# cml_gate2 : LEF d'integration unique MSPHY5973 / MSPHY4263 (alim-cml et prompt-063-leo, 29/09/2026). PIN du LEF source cml_gate2_env.lef,
# OBS recalculees depuis le metal reel du GDS (Metal1 a Metal5, vias compris), moins les PIN de la meme couche, sur le GDS enveloppe (piles et bandes d'alimentation d'alim-cml) ;
# OBS TopMetal1 = boite moins les bandes TopMetal1 VDD / VSS (broches).
VERSION 5.7 ;
  NOWIREEXTENSIONATPIN ON ;
  DIVIDERCHAR "/" ;
  BUSBITCHARS "[]" ;
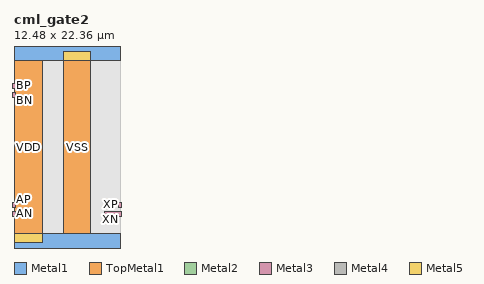
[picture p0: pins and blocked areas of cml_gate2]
MACRO cml_gate2
  CLASS BLOCK ;
  FOREIGN cml_gate2 ;
  ORIGIN 0.000 0.000 ;
  SIZE 12.480 BY 22.360 ;
  PIN VDD
    DIRECTION INOUT ;
    USE POWER ;
    PORT
      LAYER Metal1 ;
        RECT 0.000 -1.000 12.480 1.000 ;
      LAYER TopMetal1 ;
        RECT 0.100 -0.000 3.300 22.360 ;
      LAYER Metal2 ;
        RECT 0.100 0.000 3.300 1.020 ;
      LAYER Metal3 ;
        RECT 0.100 0.000 3.300 1.020 ;
      LAYER Metal4 ;
        RECT 0.100 0.000 3.300 1.020 ;
      LAYER Metal5 ;
        RECT 0.100 0.000 3.300 1.020 ;
    END
  END VDD
  PIN VSS
    DIRECTION INOUT ;
    USE GROUND ;
    PORT
      LAYER Metal1 ;
        RECT 0.000 21.360 12.480 23.360 ;
      LAYER TopMetal1 ;
        RECT 5.860 -0.000 9.060 22.360 ;
      LAYER Metal2 ;
        RECT 5.860 21.360 9.060 22.380 ;
      LAYER Metal3 ;
        RECT 5.860 21.360 9.060 22.380 ;
      LAYER Metal4 ;
        RECT 5.860 21.360 9.060 22.380 ;
      LAYER Metal5 ;
        RECT 5.860 21.360 9.060 22.380 ;
    END
  END VSS
  PIN AN
    DIRECTION INPUT ;
    USE SIGNAL ;
    ANTENNAGATEAREA 0.826800 ;
    PORT
      LAYER Metal3 ;
        RECT -0.150 3.000 0.150 3.600 ;
    END
  END AN
  PIN AP
    DIRECTION INPUT ;
    USE SIGNAL ;
    ANTENNAGATEAREA 0.826800 ;
    PORT
      LAYER Metal3 ;
        RECT -0.150 4.100 0.150 4.700 ;
    END
  END AP
  PIN XN
    DIRECTION OUTPUT ;
    USE SIGNAL ;
    ANTENNADIFFAREA 1.208400 ;
    PORT
      LAYER Metal3 ;
        RECT 10.685 3.000 12.630 3.600 ;
    END
  END XN
  PIN XP
    DIRECTION OUTPUT ;
    USE SIGNAL ;
    ANTENNADIFFAREA 2.416800 ;
    PORT
      LAYER Metal3 ;
        RECT 12.330 4.100 12.630 4.700 ;
    END
  END XP
  PIN BN
    DIRECTION INPUT ;
    USE SIGNAL ;
    ANTENNAGATEAREA 0.826800 ;
    PORT
      LAYER Metal3 ;
        RECT -0.150 17.000 0.150 17.600 ;
    END
  END BN
  PIN BP
    DIRECTION INPUT ;
    USE SIGNAL ;
    ANTENNAGATEAREA 0.826800 ;
    PORT
      LAYER Metal3 ;
        RECT -0.150 18.100 0.150 18.700 ;
    END
  END BP
  OBS
    LAYER Metal1 ;
      RECT 2.030 2.135 2.420 2.465 ;
      RECT 2.025 2.150 2.030 2.410 ;
      RECT 4.230 2.150 4.235 2.410 ;
      RECT 3.840 2.135 4.230 2.465 ;
      RECT 6.720 2.340 7.680 2.655 ;
      RECT 10.070 2.340 11.030 2.655 ;
      RECT 2.030 2.645 2.420 2.975 ;
      RECT 2.025 2.660 2.030 2.920 ;
      RECT 4.230 2.660 4.235 2.920 ;
      RECT 3.840 2.645 4.230 2.975 ;
      RECT 2.030 3.155 2.420 3.485 ;
      RECT 2.025 3.170 2.030 3.430 ;
      RECT 4.230 3.170 4.235 3.430 ;
      RECT 3.840 3.155 4.230 3.485 ;
      RECT 2.030 3.665 2.420 3.995 ;
      RECT 2.025 3.680 2.030 3.940 ;
      RECT 4.230 3.680 4.235 3.940 ;
      RECT 3.840 3.665 4.230 3.995 ;
      RECT 2.030 4.175 2.420 4.505 ;
      RECT 2.025 4.190 2.030 4.450 ;
      RECT 4.230 4.190 4.235 4.450 ;
      RECT 3.840 4.175 4.230 4.505 ;
      RECT 2.030 4.685 2.420 5.015 ;
      RECT 2.025 4.700 2.030 4.960 ;
      RECT 4.230 4.700 4.235 4.960 ;
      RECT 3.840 4.685 4.230 5.015 ;
      RECT 2.030 5.195 2.420 5.525 ;
      RECT 2.025 5.210 2.030 5.470 ;
      RECT 4.230 5.210 4.235 5.470 ;
      RECT 3.840 5.195 4.230 5.525 ;
      RECT 2.030 5.705 2.420 6.035 ;
      RECT 2.025 5.720 2.030 5.980 ;
      RECT 4.230 5.720 4.235 5.980 ;
      RECT 3.840 5.705 4.230 6.035 ;
      RECT 2.030 6.215 2.420 6.545 ;
      RECT 2.025 6.230 2.030 6.490 ;
      RECT 4.230 6.230 4.235 6.490 ;
      RECT 3.840 6.215 4.230 6.545 ;
      RECT 2.030 6.725 2.420 7.055 ;
      RECT 2.025 6.740 2.030 7.000 ;
      RECT 4.230 6.740 4.235 7.000 ;
      RECT 3.840 6.725 4.230 7.055 ;
      RECT 2.030 7.235 2.420 7.565 ;
      RECT 2.025 7.250 2.030 7.510 ;
      RECT 4.230 7.250 4.235 7.510 ;
      RECT 3.840 7.235 4.230 7.565 ;
      RECT 2.030 7.745 2.420 8.075 ;
      RECT 2.025 7.760 2.030 8.020 ;
      RECT 4.230 7.760 4.235 8.020 ;
      RECT 3.840 7.745 4.230 8.075 ;
      RECT 2.030 8.255 2.420 8.585 ;
      RECT 2.025 8.270 2.030 8.530 ;
      RECT 4.230 8.270 4.235 8.530 ;
      RECT 3.840 8.255 4.230 8.585 ;
      RECT 1.655 1.900 1.815 8.780 ;
      RECT 1.655 8.780 2.785 8.940 ;
      RECT 2.625 1.900 2.785 8.780 ;
      RECT 1.655 1.590 2.785 1.900 ;
      RECT 3.475 1.900 3.635 8.780 ;
      RECT 3.475 8.780 4.605 8.940 ;
      RECT 4.445 1.900 4.605 8.780 ;
      RECT 3.475 1.590 4.605 1.900 ;
      RECT 2.040 9.790 2.430 10.120 ;
      RECT 2.035 9.820 2.040 10.080 ;
      RECT 4.240 9.820 4.245 10.080 ;
      RECT 3.850 9.790 4.240 10.120 ;
      RECT 6.720 10.265 7.680 10.580 ;
      RECT 10.070 10.265 11.030 10.580 ;
      RECT 2.040 10.300 2.430 10.630 ;
      RECT 2.035 10.330 2.040 10.590 ;
      RECT 4.240 10.330 4.245 10.590 ;
      RECT 3.850 10.300 4.240 10.630 ;
      RECT 2.040 10.810 2.430 11.140 ;
      RECT 2.035 10.840 2.040 11.100 ;
      RECT 4.240 10.840 4.245 11.100 ;
      RECT 3.850 10.810 4.240 11.140 ;
      RECT 2.040 11.320 2.430 11.650 ;
      RECT 2.035 11.350 2.040 11.610 ;
      RECT 4.240 11.350 4.245 11.610 ;
      RECT 3.850 11.320 4.240 11.650 ;
      RECT 2.040 11.830 2.430 12.160 ;
      RECT 2.035 11.860 2.040 12.120 ;
      RECT 4.240 11.860 4.245 12.120 ;
      RECT 3.850 11.830 4.240 12.160 ;
      RECT 2.040 12.340 2.430 12.670 ;
      RECT 2.035 12.370 2.040 12.630 ;
      RECT 4.240 12.370 4.245 12.630 ;
      RECT 3.850 12.340 4.240 12.670 ;
      RECT 2.040 12.850 2.430 13.180 ;
      RECT 2.035 12.880 2.040 13.140 ;
      RECT 4.240 12.880 4.245 13.140 ;
      RECT 3.850 12.850 4.240 13.180 ;
      RECT 2.040 13.360 2.430 13.690 ;
      RECT 2.035 13.390 2.040 13.650 ;
      RECT 4.240 13.390 4.245 13.650 ;
      RECT 3.850 13.360 4.240 13.690 ;
      RECT 2.040 13.870 2.430 14.200 ;
      RECT 2.035 13.900 2.040 14.160 ;
      RECT 4.240 13.900 4.245 14.160 ;
      RECT 3.850 13.870 4.240 14.200 ;
      RECT 2.040 14.380 2.430 14.710 ;
      RECT 2.035 14.410 2.040 14.670 ;
      RECT 4.240 14.410 4.245 14.670 ;
      RECT 3.850 14.380 4.240 14.710 ;
      RECT 2.040 14.890 2.430 15.220 ;
      RECT 2.035 14.920 2.040 15.180 ;
      RECT 4.240 14.920 4.245 15.180 ;
      RECT 3.850 14.890 4.240 15.220 ;
      RECT 2.040 15.400 2.430 15.730 ;
      RECT 2.035 15.430 2.040 15.690 ;
      RECT 4.240 15.430 4.245 15.690 ;
      RECT 3.850 15.400 4.240 15.730 ;
      RECT 2.040 15.910 2.430 16.240 ;
      RECT 2.035 15.940 2.040 16.200 ;
      RECT 4.240 15.940 4.245 16.200 ;
      RECT 3.850 15.910 4.240 16.240 ;
      RECT 3.485 9.570 3.645 16.450 ;
      RECT 3.650 16.450 4.615 16.660 ;
      RECT 4.455 9.570 4.615 16.450 ;
      RECT 3.485 9.400 4.615 9.570 ;
      RECT 3.485 16.450 3.650 17.150 ;
      RECT 3.450 17.150 3.680 17.450 ;
      RECT 1.665 9.570 1.825 16.450 ;
      RECT 1.650 16.450 2.795 16.660 ;
      RECT 2.635 9.570 2.795 16.450 ;
      RECT 1.665 9.400 2.795 9.570 ;
      RECT 1.490 16.450 1.650 18.100 ;
      RECT 1.450 18.100 1.680 18.400 ;
      RECT 2.690 19.030 3.005 19.990 ;
      RECT 6.060 1.840 6.220 11.080 ;
      RECT 8.180 1.840 8.340 11.080 ;
      RECT 9.410 1.840 9.570 11.080 ;
      RECT 2.030 18.530 2.190 20.490 ;
      RECT 2.030 20.650 2.460 21.360 ;
      RECT 6.060 11.080 11.690 11.240 ;
      RECT 11.530 1.840 11.690 11.080 ;
      RECT 6.060 1.680 11.690 1.840 ;
      RECT 2.030 20.490 8.055 20.650 ;
      RECT 8.055 19.030 8.870 21.360 ;
      RECT 8.870 18.370 9.030 21.360 ;
      RECT 2.030 18.370 8.870 18.530 ;
      RECT 6.060 11.240 6.280 18.370 ;
    LAYER Via1 ;
      RECT 8.105 19.210 8.295 19.400 ;
      RECT 8.105 19.620 8.295 19.810 ;
      RECT 6.165 21.535 6.355 21.725 ;
      RECT 6.645 21.535 6.835 21.725 ;
      RECT 7.125 21.535 7.315 21.725 ;
      RECT 7.605 21.535 7.795 21.725 ;
      RECT 8.085 21.535 8.275 21.725 ;
      RECT 8.565 21.535 8.755 21.725 ;
      RECT 6.165 22.015 6.355 22.205 ;
      RECT 6.645 22.015 6.835 22.205 ;
      RECT 7.125 22.015 7.315 22.205 ;
      RECT 7.605 22.015 7.795 22.205 ;
      RECT 8.085 22.015 8.275 22.205 ;
      RECT 8.565 22.015 8.755 22.205 ;
      RECT 2.140 14.955 2.330 15.145 ;
      RECT 3.950 14.955 4.140 15.145 ;
      RECT 2.140 15.465 2.330 15.655 ;
      RECT 3.950 15.465 4.140 15.655 ;
      RECT 2.140 15.975 2.330 16.165 ;
      RECT 3.950 15.975 4.140 16.165 ;
      RECT 3.475 17.205 3.665 17.395 ;
      RECT 1.475 18.155 1.665 18.345 ;
      RECT 2.765 19.210 2.955 19.400 ;
      RECT 2.140 11.385 2.330 11.575 ;
      RECT 2.765 19.620 2.955 19.810 ;
      RECT 3.950 11.385 4.140 11.575 ;
      RECT 2.140 11.895 2.330 12.085 ;
      RECT 3.950 11.895 4.140 12.085 ;
      RECT 2.140 12.405 2.330 12.595 ;
      RECT 3.950 12.405 4.140 12.595 ;
      RECT 2.140 12.915 2.330 13.105 ;
      RECT 3.950 12.915 4.140 13.105 ;
      RECT 2.140 13.425 2.330 13.615 ;
      RECT 3.950 13.425 4.140 13.615 ;
      RECT 2.140 13.935 2.330 14.125 ;
      RECT 3.950 13.935 4.140 14.125 ;
      RECT 2.140 14.445 2.330 14.635 ;
      RECT 3.950 14.445 4.140 14.635 ;
      RECT 2.130 7.810 2.320 8.000 ;
      RECT 3.940 7.810 4.130 8.000 ;
      RECT 2.130 8.320 2.320 8.510 ;
      RECT 3.940 8.320 4.130 8.510 ;
      RECT 2.140 9.855 2.330 10.045 ;
      RECT 3.950 9.855 4.140 10.045 ;
      RECT 2.140 10.365 2.330 10.555 ;
      RECT 3.950 10.365 4.140 10.555 ;
      RECT 2.140 10.875 2.330 11.065 ;
      RECT 3.950 10.875 4.140 11.065 ;
      RECT 0.405 0.175 0.595 0.365 ;
      RECT 0.885 0.175 1.075 0.365 ;
      RECT 1.365 0.175 1.555 0.365 ;
      RECT 1.845 0.175 2.035 0.365 ;
      RECT 2.325 0.175 2.515 0.365 ;
      RECT 2.805 0.175 2.995 0.365 ;
      RECT 0.405 0.655 0.595 0.845 ;
      RECT 0.885 0.655 1.075 0.845 ;
      RECT 1.365 0.655 1.555 0.845 ;
      RECT 1.845 0.655 2.035 0.845 ;
      RECT 2.325 0.655 2.515 0.845 ;
      RECT 2.805 0.655 2.995 0.845 ;
      RECT 1.760 1.660 1.950 1.850 ;
      RECT 2.200 1.660 2.390 1.850 ;
      RECT 3.540 1.660 3.730 1.850 ;
      RECT 3.980 1.660 4.170 1.850 ;
      RECT 2.130 2.200 2.320 2.390 ;
      RECT 3.940 2.200 4.130 2.390 ;
      RECT 2.130 2.710 2.320 2.900 ;
      RECT 3.940 2.710 4.130 2.900 ;
      RECT 2.130 3.220 2.320 3.410 ;
      RECT 3.940 3.220 4.130 3.410 ;
      RECT 2.130 3.730 2.320 3.920 ;
      RECT 3.940 3.730 4.130 3.920 ;
      RECT 2.130 4.240 2.320 4.430 ;
      RECT 3.940 4.240 4.130 4.430 ;
      RECT 2.130 4.750 2.320 4.940 ;
      RECT 3.940 4.750 4.130 4.940 ;
      RECT 2.130 5.260 2.320 5.450 ;
      RECT 3.940 5.260 4.130 5.450 ;
      RECT 2.130 5.770 2.320 5.960 ;
      RECT 3.940 5.770 4.130 5.960 ;
      RECT 2.130 6.280 2.320 6.470 ;
      RECT 3.940 6.280 4.130 6.470 ;
      RECT 2.130 6.790 2.320 6.980 ;
      RECT 3.940 6.790 4.130 6.980 ;
      RECT 2.130 7.300 2.320 7.490 ;
      RECT 3.940 7.300 4.130 7.490 ;
      RECT 10.135 0.705 10.325 0.895 ;
      RECT 10.775 0.705 10.965 0.895 ;
      RECT 6.900 10.315 7.090 10.505 ;
      RECT 7.310 10.315 7.500 10.505 ;
      RECT 10.250 10.315 10.440 10.505 ;
      RECT 10.660 10.315 10.850 10.505 ;
      RECT 10.135 0.285 10.325 0.475 ;
      RECT 10.775 0.285 10.965 0.475 ;
      RECT 6.785 0.285 6.975 0.475 ;
      RECT 7.425 0.285 7.615 0.475 ;
      RECT 6.785 0.705 6.975 0.895 ;
      RECT 7.425 0.705 7.615 0.895 ;
      RECT 6.900 2.415 7.090 2.605 ;
      RECT 7.310 2.415 7.500 2.605 ;
      RECT 10.250 2.415 10.440 2.605 ;
      RECT 10.660 2.415 10.850 2.605 ;
    LAYER Metal2 ;
      RECT 2.910 1.620 4.230 1.890 ;
      RECT 6.770 0.230 7.630 2.695 ;
      RECT 10.120 0.230 10.980 2.695 ;
      RECT 0.400 1.610 2.450 1.900 ;
      RECT 0.400 1.900 0.710 4.400 ;
      RECT 1.370 4.735 2.380 4.955 ;
      RECT 1.370 6.775 2.380 6.995 ;
      RECT 1.370 5.755 2.380 5.975 ;
      RECT 1.370 3.715 2.380 3.935 ;
      RECT 1.150 2.695 2.380 2.915 ;
      RECT 1.150 2.915 1.370 7.795 ;
      RECT 1.000 2.915 1.150 6.995 ;
      RECT 1.150 7.795 2.380 8.015 ;
      RECT 10.120 10.225 10.980 10.595 ;
      RECT 10.400 3.000 10.750 10.225 ;
      RECT 1.380 8.305 4.190 8.525 ;
      RECT 1.380 8.525 3.350 8.670 ;
      RECT 2.910 7.505 3.350 8.305 ;
      RECT 2.070 7.285 4.190 7.505 ;
      RECT 2.910 6.485 3.350 7.285 ;
      RECT 2.070 6.265 4.190 6.485 ;
      RECT 2.910 5.465 3.350 6.265 ;
      RECT 2.070 5.245 4.190 5.465 ;
      RECT 2.910 4.445 3.350 5.245 ;
      RECT 2.070 4.225 4.190 4.445 ;
      RECT 2.910 3.425 3.350 4.225 ;
      RECT 2.070 3.205 4.190 3.425 ;
      RECT 2.910 2.405 3.350 3.205 ;
      RECT 2.070 2.185 4.190 2.405 ;
      RECT 1.380 11.370 2.390 11.590 ;
      RECT 1.380 14.430 2.390 14.650 ;
      RECT 1.380 13.410 2.390 13.630 ;
      RECT 1.380 12.390 2.390 12.610 ;
      RECT 1.380 10.350 2.390 10.570 ;
      RECT 1.060 8.305 1.380 15.450 ;
      RECT 1.060 15.450 2.390 15.670 ;
      RECT 5.270 10.110 7.720 10.680 ;
      RECT 3.880 3.715 4.900 3.935 ;
      RECT 3.880 4.735 4.900 4.955 ;
      RECT 3.880 5.755 4.900 5.975 ;
      RECT 3.880 6.775 4.900 6.995 ;
      RECT 3.880 7.795 4.900 8.015 ;
      RECT 3.890 10.350 4.900 10.570 ;
      RECT 3.890 11.370 4.900 11.590 ;
      RECT 3.890 12.390 4.900 12.610 ;
      RECT 3.890 13.410 4.900 13.630 ;
      RECT 3.890 14.430 4.900 14.650 ;
      RECT 3.890 15.450 5.270 15.670 ;
      RECT 4.900 2.915 5.270 15.450 ;
      RECT 3.880 2.695 5.270 2.915 ;
      RECT 3.410 17.150 3.720 17.650 ;
      RECT 1.410 18.100 1.720 18.600 ;
      RECT 2.080 15.960 4.200 16.180 ;
      RECT 2.920 15.160 3.360 15.960 ;
      RECT 2.080 14.940 4.200 15.160 ;
      RECT 2.675 19.080 3.190 19.940 ;
      RECT 2.750 16.180 3.190 19.080 ;
      RECT 2.920 14.140 3.360 14.940 ;
      RECT 2.080 13.920 4.200 14.140 ;
      RECT 2.920 13.120 3.360 13.920 ;
      RECT 2.080 12.900 4.200 13.120 ;
      RECT 2.920 12.100 3.360 12.900 ;
      RECT 2.080 11.880 4.200 12.100 ;
      RECT 2.920 11.080 3.360 11.880 ;
      RECT 2.080 10.860 4.200 11.080 ;
      RECT 2.920 10.060 3.360 10.860 ;
      RECT 2.080 9.840 4.200 10.060 ;
      RECT 8.015 19.080 8.385 19.940 ;
    LAYER Via2 ;
      RECT 0.405 0.175 0.595 0.365 ;
      RECT 0.885 0.175 1.075 0.365 ;
      RECT 1.365 0.175 1.555 0.365 ;
      RECT 1.845 0.175 2.035 0.365 ;
      RECT 2.325 0.175 2.515 0.365 ;
      RECT 2.805 0.175 2.995 0.365 ;
      RECT 0.405 0.655 0.595 0.845 ;
      RECT 0.885 0.655 1.075 0.845 ;
      RECT 1.365 0.655 1.555 0.845 ;
      RECT 1.845 0.655 2.035 0.845 ;
      RECT 2.325 0.655 2.515 0.845 ;
      RECT 2.805 0.655 2.995 0.845 ;
      RECT 3.040 1.660 3.230 1.850 ;
      RECT 3.460 1.660 3.650 1.850 ;
      RECT 10.490 3.080 10.680 3.270 ;
      RECT 10.490 3.500 10.680 3.690 ;
      RECT 0.460 3.720 0.650 3.910 ;
      RECT 0.460 4.140 0.650 4.330 ;
      RECT 4.990 4.350 5.180 4.540 ;
      RECT 4.990 4.780 5.180 4.970 ;
      RECT 1.090 4.960 1.280 5.150 ;
      RECT 1.090 5.390 1.280 5.580 ;
      RECT 3.475 17.205 3.665 17.395 ;
      RECT 1.475 18.155 1.665 18.345 ;
      RECT 6.165 21.535 6.355 21.725 ;
      RECT 6.645 21.535 6.835 21.725 ;
      RECT 7.125 21.535 7.315 21.725 ;
      RECT 7.605 21.535 7.795 21.725 ;
      RECT 8.085 21.535 8.275 21.725 ;
      RECT 8.565 21.535 8.755 21.725 ;
      RECT 6.165 22.015 6.355 22.205 ;
      RECT 6.645 22.015 6.835 22.205 ;
      RECT 7.125 22.015 7.315 22.205 ;
      RECT 7.605 22.015 7.795 22.205 ;
      RECT 8.085 22.015 8.275 22.205 ;
      RECT 8.565 22.015 8.755 22.205 ;
    LAYER Metal3 ;
      RECT 0.150 3.000 2.960 3.300 ;
      RECT 2.960 1.610 3.780 1.910 ;
      RECT 2.960 1.910 3.260 3.300 ;
      RECT 0.150 4.100 0.710 4.400 ;
      RECT 0.400 3.630 0.710 4.100 ;
      RECT 5.300 4.250 12.330 4.700 ;
      RECT 4.900 4.250 5.300 5.030 ;
      RECT 4.460 3.470 10.250 3.790 ;
      RECT 10.250 3.000 10.685 3.600 ;
      RECT 10.250 3.600 10.760 3.790 ;
      RECT 1.370 4.880 4.160 5.180 ;
      RECT 1.000 4.880 1.370 5.640 ;
      RECT 4.160 3.470 4.460 5.180 ;
      RECT 0.150 17.150 3.720 17.450 ;
      RECT 0.150 18.100 1.720 18.400 ;
    LAYER Via3 ;
      RECT 0.405 0.175 0.595 0.365 ;
      RECT 0.885 0.175 1.075 0.365 ;
      RECT 1.365 0.175 1.555 0.365 ;
      RECT 1.845 0.175 2.035 0.365 ;
      RECT 2.325 0.175 2.515 0.365 ;
      RECT 2.805 0.175 2.995 0.365 ;
      RECT 0.405 0.655 0.595 0.845 ;
      RECT 0.885 0.655 1.075 0.845 ;
      RECT 1.365 0.655 1.555 0.845 ;
      RECT 1.845 0.655 2.035 0.845 ;
      RECT 2.325 0.655 2.515 0.845 ;
      RECT 2.805 0.655 2.995 0.845 ;
      RECT 6.165 21.535 6.355 21.725 ;
      RECT 6.645 21.535 6.835 21.725 ;
      RECT 7.125 21.535 7.315 21.725 ;
      RECT 7.605 21.535 7.795 21.725 ;
      RECT 8.085 21.535 8.275 21.725 ;
      RECT 8.565 21.535 8.755 21.725 ;
      RECT 6.165 22.015 6.355 22.205 ;
      RECT 6.645 22.015 6.835 22.205 ;
      RECT 7.125 22.015 7.315 22.205 ;
      RECT 7.605 22.015 7.795 22.205 ;
      RECT 8.085 22.015 8.275 22.205 ;
      RECT 8.565 22.015 8.755 22.205 ;
    LAYER Via4 ;
      RECT 0.405 0.175 0.595 0.365 ;
      RECT 0.885 0.175 1.075 0.365 ;
      RECT 1.365 0.175 1.555 0.365 ;
      RECT 1.845 0.175 2.035 0.365 ;
      RECT 2.325 0.175 2.515 0.365 ;
      RECT 2.805 0.175 2.995 0.365 ;
      RECT 0.405 0.655 0.595 0.845 ;
      RECT 0.885 0.655 1.075 0.845 ;
      RECT 1.365 0.655 1.555 0.845 ;
      RECT 1.845 0.655 2.035 0.845 ;
      RECT 2.325 0.655 2.515 0.845 ;
      RECT 2.805 0.655 2.995 0.845 ;
      RECT 6.165 21.535 6.355 21.725 ;
      RECT 6.645 21.535 6.835 21.725 ;
      RECT 7.125 21.535 7.315 21.725 ;
      RECT 7.605 21.535 7.795 21.725 ;
      RECT 8.085 21.535 8.275 21.725 ;
      RECT 8.565 21.535 8.755 21.725 ;
      RECT 6.165 22.015 6.355 22.205 ;
      RECT 6.645 22.015 6.835 22.205 ;
      RECT 7.125 22.015 7.315 22.205 ;
      RECT 7.605 22.015 7.795 22.205 ;
      RECT 8.085 22.015 8.275 22.205 ;
      RECT 8.565 22.015 8.755 22.205 ;
    LAYER TopMetal1 ;
      RECT 0.000 0.000 0.100 22.360 ;
      RECT 3.300 0.000 5.860 22.360 ;
      RECT 9.060 0.000 12.480 22.360 ;
  END
END cml_gate2
END LIBRARY

